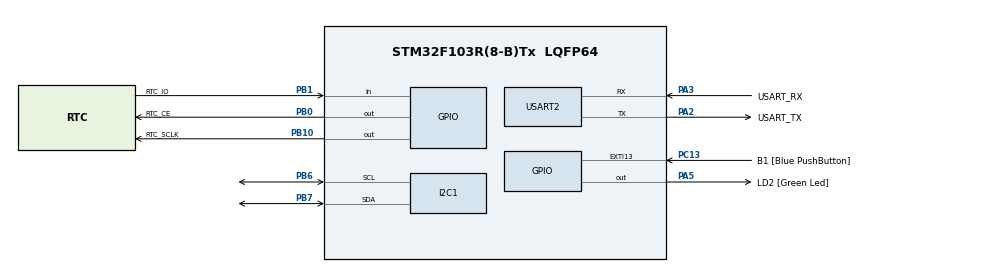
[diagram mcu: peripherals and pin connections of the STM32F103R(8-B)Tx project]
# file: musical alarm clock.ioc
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Mcu.Family=STM32F1
Mcu.Name=STM32F103R(8-B)Tx
Mcu.Package=LQFP64
NVIC.EXTI15_10_IRQn=true\:0\:0\:false\:false\:true\:true\:true\:true
NVIC.PriorityGroup=NVIC_PRIORITYGROUP_4
PA13.GPIO_Label=TMS
PA13.Mode=Serial_Wire
PA13.Signal=SYS_JTMS-SWDIO
PA14.GPIO_Label=TCK
PA14.Mode=Serial_Wire
PA14.Signal=SYS_JTCK-SWCLK
PA2.GPIO_Label=USART_TX
PA2.GPIO_Mode=GPIO_MODE_AF_PP
PA2.GPIO_PuPd=GPIO_NOPULL
PA2.GPIO_Speed=GPIO_SPEED_FREQ_LOW
PA2.Mode=Asynchronous
PA2.Signal=USART2_TX
PA3.GPIO_Label=USART_RX
PA3.GPIO_Mode=GPIO_MODE_AF_PP
PA3.GPIO_PuPd=GPIO_NOPULL
PA3.GPIO_Speed=GPIO_SPEED_FREQ_LOW
PA3.Mode=Asynchronous
PA3.Signal=USART2_RX
PA5.GPIO_Label=LD2 [Green Led]
PA5.GPIO_ModeDefaultOutputPP=GPIO_MODE_OUTPUT_PP
PA5.GPIO_PuPd=GPIO_NOPULL
PA5.GPIO_Speed=GPIO_SPEED_FREQ_LOW
PA5.Signal=GPIO_Output
PB0.GPIO_Label=RTC_CE
PB0.Signal=GPIO_Output
PB1.GPIO_Label=RTC_IO
PB1.GPIO_PuPd=GPIO_NOPULL
PB1.Signal=GPIO_Input
PB10.GPIO_Label=RTC_SCLK
PB10.Signal=GPIO_Output
PB3.GPIO_Label=SWO
PB3.Signal=SYS_JTDO-TRACESWO
PB6.Mode=I2C
PB6.Signal=I2C1_SCL
PB7.Mode=I2C
PB7.Signal=I2C1_SDA
PC13-TAMPER-RTC.GPIO_Label=B1 [Blue PushButton]
PC13-TAMPER-RTC.GPIO_PuPd=GPIO_NOPULL
PC13-TAMPER-RTC.Signal=GPXTI13
PC14-OSC32_IN.Mode=LSE-External-Oscillator
PC14-OSC32_IN.Signal=RCC_OSC32_IN
PC15-OSC32_OUT.Mode=LSE-External-Oscillator
PC15-OSC32_OUT.Signal=RCC_OSC32_OUT
PD0-OSC_IN.Mode=HSE-External-Clock-Source
PD0-OSC_IN.Signal=RCC_OSC_IN
PD1-OSC_OUT.Mode=HSE-External-Clock-Source
PD1-OSC_OUT.Signal=RCC_OSC_OUT
ProjectManager.HeapSize=0x200
ProjectManager.StackSize=0x400
ProjectManager.TargetToolchain=STM32CubeIDE
RCC.AHBFreq_Value=64000000
RCC.APB1CLKDivider=RCC_HCLK_DIV2
RCC.APB1Freq_Value=32000000
RCC.APB1TimFreq_Value=64000000
RCC.APB2Freq_Value=64000000
RCC.APB2TimFreq_Value=64000000
RCC.HCLKFreq_Value=64000000
RCC.HSE_VALUE=3072000
RCC.PLLMUL=RCC_PLL_MUL16
RCC.RTCClockSelection=RCC_RTCCLKSOURCE_LSE
RCC.SYSCLKFreq_VALUE=64000000
RCC.SYSCLKSource=RCC_SYSCLKSOURCE_PLLCLK
RCC.USBFreq_Value=64000000
USART2.VirtualMode=VM_ASYNC
board=NUCLEO-F103RB

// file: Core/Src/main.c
/* USER CODE BEGIN Header */
/**
  ******************************************************************************
  * @file           : main.c
  * @brief          : Main program body
  ******************************************************************************
  * @attention
  *
  * Copyright (c) 2026 STMicroelectronics.
  * All rights reserved.
  *
  * This software is licensed under terms that can be found in the LICENSE file
  * in the root directory of this software component.
  * If no LICENSE file comes with this software, it is provided AS-IS.
  *
  ******************************************************************************
  */
/* USER CODE END Header */
#include "main.h"

/* USER CODE BEGIN Includes */
#include "app_main.h"
/* USER CODE END Includes */

I2C_HandleTypeDef hi2c1;

UART_HandleTypeDef huart2;

void SystemClock_Config(void);
static void MX_GPIO_Init(void);
static void MX_USART2_UART_Init(void);
static void MX_I2C1_Init(void);

/* USER CODE BEGIN 0 */

// 重新導向 printf 到 UART2
int __io_putchar(int ch)
{
  HAL_UART_Transmit(&huart2, (uint8_t *)&ch, 1, 0xFFFF);
  return ch;
}
/* USER CODE END 0 */

int main(void)
{

  /* MCU Configuration--------------------------------------------------------*/

  /* Reset of all peripherals, Initializes the Flash interface and the Systick. */
  HAL_Init();

  /* Configure the system clock */
  SystemClock_Config();

  /* Initialize all configured peripherals */
  MX_GPIO_Init();
  MX_USART2_UART_Init();
  MX_I2C1_Init();
  /* USER CODE BEGIN 2 */

  // 呼叫應用層初始化
  App_Init();
  /* USER CODE END 2 */

  /* Infinite loop */
  /* USER CODE BEGIN WHILE */
  while (1)
  {
    // 呼叫應用層主迴圈
    App_Loop();
    /* USER CODE END WHILE */

  }
}

void SystemClock_Config(void)
{
  RCC_OscInitTypeDef RCC_OscInitStruct = {0};
  RCC_ClkInitTypeDef RCC_ClkInitStruct = {0};

  /** Initializes the RCC Oscillators according to the specified parameters
  * in the RCC_OscInitTypeDef structure.
  */
  RCC_OscInitStruct.OscillatorType = RCC_OSCILLATORTYPE_HSE;
  RCC_OscInitStruct.HSEState = RCC_HSE_BYPASS;
  RCC_OscInitStruct.HSEPredivValue = RCC_HSE_PREDIV_DIV1;
  RCC_OscInitStruct.PLL.PLLState = RCC_PLL_ON;
  RCC_OscInitStruct.PLL.PLLSource = RCC_PLLSOURCE_HSE;
  RCC_OscInitStruct.PLL.PLLMUL = RCC_PLL_MUL16;
  if (HAL_RCC_OscConfig(&RCC_OscInitStruct) != HAL_OK)
  {
    Error_Handler();
  }

  /** Initializes the CPU, AHB and APB buses clocks
  */
  RCC_ClkInitStruct.ClockType = RCC_CLOCKTYPE_HCLK|RCC_CLOCKTYPE_SYSCLK
                              |RCC_CLOCKTYPE_PCLK1|RCC_CLOCKTYPE_PCLK2;
  RCC_ClkInitStruct.SYSCLKSource = RCC_SYSCLKSOURCE_PLLCLK;
  RCC_ClkInitStruct.AHBCLKDivider = RCC_SYSCLK_DIV1;
  RCC_ClkInitStruct.APB1CLKDivider = RCC_HCLK_DIV2;
  RCC_ClkInitStruct.APB2CLKDivider = RCC_HCLK_DIV1;

  if (HAL_RCC_ClockConfig(&RCC_ClkInitStruct, FLASH_LATENCY_2) != HAL_OK)
  {
    Error_Handler();
  }

  /* 輸出系統時鐘到 PA8 (MCO Pin) 以供量測 debug */
  // HAL_RCC_MCOConfig(RCC_MCO1, RCC_MCO1SOURCE_SYSCLK, RCC_MCODIV_1);
}

static void MX_I2C1_Init(void)
{

  hi2c1.Instance = I2C1;
  hi2c1.Init.ClockSpeed = 100000;
  hi2c1.Init.DutyCycle = I2C_DUTYCYCLE_2;
  hi2c1.Init.OwnAddress1 = 0;
  hi2c1.Init.AddressingMode = I2C_ADDRESSINGMODE_7BIT;
  hi2c1.Init.DualAddressMode = I2C_DUALADDRESS_DISABLE;
  hi2c1.Init.OwnAddress2 = 0;
  hi2c1.Init.GeneralCallMode = I2C_GENERALCALL_DISABLE;
  hi2c1.Init.NoStretchMode = I2C_NOSTRETCH_DISABLE;
  if (HAL_I2C_Init(&hi2c1) != HAL_OK)
  {
    Error_Handler();
  }

}

static void MX_USART2_UART_Init(void)
{

  huart2.Instance = USART2;
  huart2.Init.BaudRate = 115200;
  huart2.Init.WordLength = UART_WORDLENGTH_8B;
  huart2.Init.StopBits = UART_STOPBITS_1;
  huart2.Init.Parity = UART_PARITY_NONE;
  huart2.Init.Mode = UART_MODE_TX_RX;
  huart2.Init.HwFlowCtl = UART_HWCONTROL_NONE;
  huart2.Init.OverSampling = UART_OVERSAMPLING_16;
  if (HAL_UART_Init(&huart2) != HAL_OK)
  {
    Error_Handler();
  }

}

static void MX_GPIO_Init(void)
{
  GPIO_InitTypeDef GPIO_InitStruct = {0};

  /* GPIO Ports Clock Enable */
  __HAL_RCC_GPIOC_CLK_ENABLE();
  __HAL_RCC_GPIOD_CLK_ENABLE();
  __HAL_RCC_GPIOA_CLK_ENABLE();
  __HAL_RCC_GPIOB_CLK_ENABLE();

  /*Configure GPIO pin Output Level */
  HAL_GPIO_WritePin(LD2_GPIO_Port, LD2_Pin, GPIO_PIN_RESET);

  /*Configure GPIO pin : B1_Pin */
  GPIO_InitStruct.Pin = B1_Pin;
  GPIO_InitStruct.Mode = GPIO_MODE_IT_RISING;
  GPIO_InitStruct.Pull = GPIO_NOPULL;
  HAL_GPIO_Init(B1_GPIO_Port, &GPIO_InitStruct);

  /*Configure GPIO pin : LD2_Pin */
  GPIO_InitStruct.Pin = LD2_Pin;
  GPIO_InitStruct.Mode = GPIO_MODE_OUTPUT_PP;
  GPIO_InitStruct.Pull = GPIO_NOPULL;
  GPIO_InitStruct.Speed = GPIO_SPEED_FREQ_LOW;
  HAL_GPIO_Init(LD2_GPIO_Port, &GPIO_InitStruct);

  /* EXTI interrupt init*/
  HAL_NVIC_SetPriority(EXTI15_10_IRQn, 0, 0);
  HAL_NVIC_EnableIRQ(EXTI15_10_IRQn);

}

void Error_Handler(void)
{
  __disable_irq();
  while (1)
  {
  }
}
